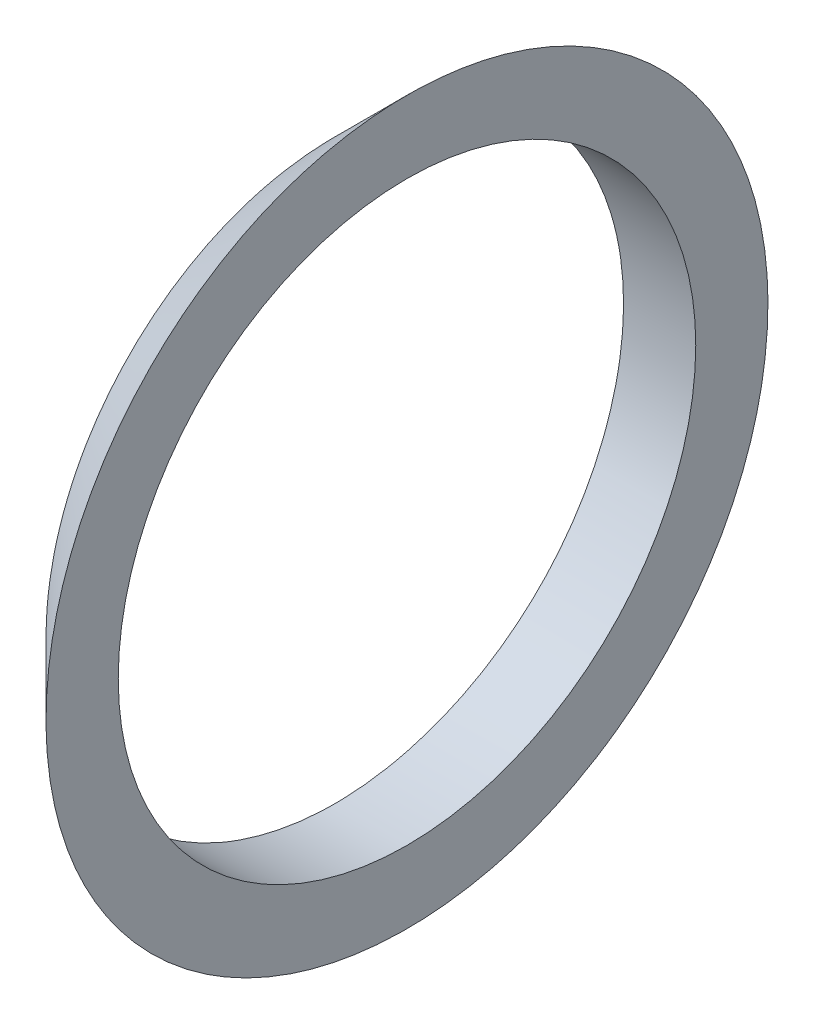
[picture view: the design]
ISO-10303-21;
HEADER;
FILE_DESCRIPTION(('STEP AP214'),'2;1');
FILE_NAME('part.step','',(''),(''),'','','');
FILE_SCHEMA(('AUTOMOTIVE_DESIGN { 1 0 10303 214 1 1 1 1 }'));
ENDSEC;
DATA;
#1=APPLICATION_CONTEXT('core data for automotive mechanical design processes');
#2=APPLICATION_PROTOCOL_DEFINITION('international standard','automotive_design',2000,#1);
#3=PRODUCT_CONTEXT('',#1,'mechanical');
#4=PRODUCT('Part','Part','',(#3));
#5=PRODUCT_RELATED_PRODUCT_CATEGORY('part','',(#4));
#6=PRODUCT_DEFINITION_FORMATION('','',#4);
#7=PRODUCT_DEFINITION_CONTEXT('part definition',#1,'design');
#8=PRODUCT_DEFINITION('design','',#6,#7);
#9=PRODUCT_DEFINITION_SHAPE('','',#8);
#10=(LENGTH_UNIT() NAMED_UNIT(*) SI_UNIT(.MILLI.,.METRE.));
#11=(NAMED_UNIT(*) PLANE_ANGLE_UNIT() SI_UNIT($,.RADIAN.));
#12=(NAMED_UNIT(*) SI_UNIT($,.STERADIAN.) SOLID_ANGLE_UNIT());
#13=UNCERTAINTY_MEASURE_WITH_UNIT(LENGTH_MEASURE(1.E-05),#10,'distance_accuracy_value','');
#14=(GEOMETRIC_REPRESENTATION_CONTEXT(3) GLOBAL_UNCERTAINTY_ASSIGNED_CONTEXT((#13)) GLOBAL_UNIT_ASSIGNED_CONTEXT((#10,
#11,#12)) REPRESENTATION_CONTEXT('',''));
#15=CARTESIAN_POINT('',(0.,0.,0.));
#16=DIRECTION('',(0.,0.,1.));
#17=DIRECTION('',(1.,0.,0.));
#18=AXIS2_PLACEMENT_3D('',#15,#16,#17);
#19=CARTESIAN_POINT('',(112.,55.,-23.));
#20=DIRECTION('',(1.,0.,0.));
#21=DIRECTION('',(0.,0.,-1.));
#22=AXIS2_PLACEMENT_3D('',#19,#20,#21);
#23=PLANE('',#22);
#24=CARTESIAN_POINT('',(112.,0.,19.9998724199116));
#25=CARTESIAN_POINT('',(112.,0.244989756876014,19.9998783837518));
#26=CARTESIAN_POINT('',(112.,0.48995497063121,19.995508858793));
#27=CARTESIAN_POINT('',(112.,0.979565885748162,19.9778506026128));
#28=CARTESIAN_POINT('',(112.,1.22421160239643,19.9645623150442));
#29=CARTESIAN_POINT('',(112.,1.71283709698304,19.9290391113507));
#30=CARTESIAN_POINT('',(112.,1.95681691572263,19.9068047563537));
#31=CARTESIAN_POINT('',(112.,2.44383325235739,19.8534078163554));
#32=CARTESIAN_POINT('',(112.,2.68686957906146,19.8222435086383));
#33=CARTESIAN_POINT('',(112.,3.41415854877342,19.7153111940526));
#34=CARTESIAN_POINT('',(112.,3.89651224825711,19.6261095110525));
#35=CARTESIAN_POINT('',(112.,4.85324910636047,19.4122585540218));
#36=CARTESIAN_POINT('',(112.,5.32763197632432,19.2876079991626));
#37=CARTESIAN_POINT('',(112.,6.3348788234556,18.982590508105));
#38=CARTESIAN_POINT('',(112.,6.86608978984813,18.7967271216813));
#39=CARTESIAN_POINT('',(112.,7.91085705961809,18.3805997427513));
#40=CARTESIAN_POINT('',(112.,8.42441159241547,18.1503313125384));
#41=CARTESIAN_POINT('',(112.,9.4304440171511,17.6471066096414));
#42=CARTESIAN_POINT('',(112.,9.92291258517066,17.37413169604));
#43=CARTESIAN_POINT('',(112.,10.8831031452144,16.7877001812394));
#44=CARTESIAN_POINT('',(112.,11.3508256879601,16.4742444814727));
#45=CARTESIAN_POINT('',(112.,12.2566972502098,15.8104072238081));
#46=CARTESIAN_POINT('',(112.,12.6949465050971,15.4601624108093));
#47=CARTESIAN_POINT('',(112.,13.540730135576,14.7243493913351));
#48=CARTESIAN_POINT('',(112.,13.9482637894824,14.338780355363));
#49=CARTESIAN_POINT('',(112.,14.7297504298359,13.535048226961));
#50=CARTESIAN_POINT('',(112.,15.1037058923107,13.1168875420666));
#51=CARTESIAN_POINT('',(112.,15.8153610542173,12.2507735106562));
#52=CARTESIAN_POINT('',(112.,16.1530612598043,11.8028205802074));
#53=CARTESIAN_POINT('',(112.,16.7926480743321,10.8758849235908));
#54=CARTESIAN_POINT('',(112.,17.0941722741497,10.3966522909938));
#55=CARTESIAN_POINT('',(112.,17.6556360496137,9.41433884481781));
#56=CARTESIAN_POINT('',(112.,17.9155761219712,8.91125831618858));
#57=CARTESIAN_POINT('',(112.,18.2727886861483,8.14162564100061));
#58=CARTESIAN_POINT('',(112.,18.3864218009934,7.88254695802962));
#59=CARTESIAN_POINT('',(112.,18.6025492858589,7.35984065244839));
#60=CARTESIAN_POINT('',(112.,18.7050465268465,7.09621422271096));
#61=CARTESIAN_POINT('',(112.,18.8986326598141,6.56479242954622));
#62=CARTESIAN_POINT('',(112.,18.9897209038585,6.29699683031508));
#63=CARTESIAN_POINT('',(112.,19.1602610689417,5.75772578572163));
#64=CARTESIAN_POINT('',(112.,19.2397130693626,5.48625036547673));
#65=CARTESIAN_POINT('',(112.,19.3860625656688,4.94295472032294));
#66=CARTESIAN_POINT('',(112.,19.4530816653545,4.6711672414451));
#67=CARTESIAN_POINT('',(112.,19.5754672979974,4.12498736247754));
#68=CARTESIAN_POINT('',(112.,19.6308340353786,3.8505950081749));
#69=CARTESIAN_POINT('',(112.,19.7299923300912,3.29971527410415));
#70=CARTESIAN_POINT('',(112.,19.7737832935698,3.02322778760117));
#71=CARTESIAN_POINT('',(112.,19.8498797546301,2.46867316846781));
#72=CARTESIAN_POINT('',(112.,19.8821850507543,2.19060600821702));
#73=CARTESIAN_POINT('',(112.,19.9352950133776,1.63329917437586));
#74=CARTESIAN_POINT('',(112.,19.9560965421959,1.35405920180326));
#75=CARTESIAN_POINT('',(112.,19.9861042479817,0.794960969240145));
#76=CARTESIAN_POINT('',(112.,19.9953106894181,0.515102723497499));
#77=CARTESIAN_POINT('',(112.,20.0019069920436,-0.0447562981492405));
#78=CARTESIAN_POINT('',(112.,19.9992967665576,-0.324757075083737));
#79=CARTESIAN_POINT('',(112.,19.9823608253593,-0.884406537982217));
#80=CARTESIAN_POINT('',(112.,19.9680348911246,-1.1640552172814));
#81=CARTESIAN_POINT('',(112.,19.9276889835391,-1.72455345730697));
#82=CARTESIAN_POINT('',(112.,19.9015846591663,-2.00539694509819));
#83=CARTESIAN_POINT('',(112.,19.8377117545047,-2.56575274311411));
#84=CARTESIAN_POINT('',(112.,19.7999431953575,-2.84526505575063));
#85=CARTESIAN_POINT('',(112.,19.7127211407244,-3.40245829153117));
#86=CARTESIAN_POINT('',(112.,19.6632680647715,-3.68013928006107));
#87=CARTESIAN_POINT('',(112.,19.5525534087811,-4.23311645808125));
#88=CARTESIAN_POINT('',(112.,19.4912919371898,-4.50841266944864));
#89=CARTESIAN_POINT('',(112.,19.289852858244,-5.32976534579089));
#90=CARTESIAN_POINT('',(112.,19.1319720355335,-5.87159756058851));
#91=CARTESIAN_POINT('',(112.,18.7703120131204,-6.93964824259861));
#92=CARTESIAN_POINT('',(112.,18.5665306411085,-7.4658659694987));
#93=CARTESIAN_POINT('',(112.,18.1169595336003,-8.49532083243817));
#94=CARTESIAN_POINT('',(112.,17.871497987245,-8.99870127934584));
#95=CARTESIAN_POINT('',(112.,17.3393324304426,-9.98314516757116));
#96=CARTESIAN_POINT('',(112.,17.0526298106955,-10.4642093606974));
#97=CARTESIAN_POINT('',(112.,16.439817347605,-11.4007904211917));
#98=CARTESIAN_POINT('',(112.,16.1136936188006,-11.8562982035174));
#99=CARTESIAN_POINT('',(112.,15.4245227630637,-12.7384810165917));
#100=CARTESIAN_POINT('',(112.,15.0614744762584,-13.1651551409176));
#101=CARTESIAN_POINT('',(112.,14.2984375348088,-13.9897677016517));
#102=CARTESIAN_POINT('',(112.,13.8982036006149,-14.3874791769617));
#103=CARTESIAN_POINT('',(112.,13.0658328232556,-15.1479663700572));
#104=CARTESIAN_POINT('',(112.,12.6336968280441,-15.5107430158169));
#105=CARTESIAN_POINT('',(112.,11.7405266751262,-16.1985447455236));
#106=CARTESIAN_POINT('',(112.,11.2794999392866,-16.5235794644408));
#107=CARTESIAN_POINT('',(112.,10.331641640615,-17.1335984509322));
#108=CARTESIAN_POINT('',(112.,9.84480886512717,-17.418580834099));
#109=CARTESIAN_POINT('',(112.,8.84763244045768,-17.9471688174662));
#110=CARTESIAN_POINT('',(112.,8.33723378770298,-18.1906706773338));
#111=CARTESIAN_POINT('',(112.,7.29768194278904,-18.6335359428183));
#112=CARTESIAN_POINT('',(112.,6.76853009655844,-18.832902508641));
#113=CARTESIAN_POINT('',(112.,5.69484104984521,-19.1853814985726));
#114=CARTESIAN_POINT('',(112.,5.15030126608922,-19.3384861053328));
#115=CARTESIAN_POINT('',(112.,4.32527090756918,-19.532519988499));
#116=CARTESIAN_POINT('',(112.,4.04885124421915,-19.5912665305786));
#117=CARTESIAN_POINT('',(112.,3.49373972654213,-19.6969307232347));
#118=CARTESIAN_POINT('',(112.,3.21504785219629,-19.7438482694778));
#119=CARTESIAN_POINT('',(112.,2.65960417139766,-19.8254302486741));
#120=CARTESIAN_POINT('',(112.,2.38287459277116,-19.8602467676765));
#121=CARTESIAN_POINT('',(112.,1.82821719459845,-19.9184663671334));
#122=CARTESIAN_POINT('',(112.,1.55028937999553,-19.9418694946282));
#123=CARTESIAN_POINT('',(112.,0.993708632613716,-19.977200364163));
#124=CARTESIAN_POINT('',(112.,0.715055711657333,-19.9891282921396));
#125=CARTESIAN_POINT('',(112.,0.157496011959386,-20.001310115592));
#126=CARTESIAN_POINT('',(112.,-0.121410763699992,-20.0015641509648));
#127=CARTESIAN_POINT('',(112.,-0.678971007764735,-19.9903886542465));
#128=CARTESIAN_POINT('',(112.,-0.957624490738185,-19.9789598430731));
#129=CARTESIAN_POINT('',(112.,-1.51422688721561,-19.944624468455));
#130=CARTESIAN_POINT('',(112.,-1.79217578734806,-19.9217176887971));
#131=CARTESIAN_POINT('',(112.,-2.34689854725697,-19.8644900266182));
#132=CARTESIAN_POINT('',(112.,-2.62367239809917,-19.8301690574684));
#133=CARTESIAN_POINT('',(112.,-3.17556419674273,-19.750120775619));
#134=CARTESIAN_POINT('',(112.,-3.45068216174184,-19.7043935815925));
#135=CARTESIAN_POINT('',(112.,-4.00382788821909,-19.6004656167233));
#136=CARTESIAN_POINT('',(112.,-4.28181531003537,-19.5420497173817));
#137=CARTESIAN_POINT('',(112.,-4.83500087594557,-19.4132332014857));
#138=CARTESIAN_POINT('',(112.,-5.11019901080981,-19.3428325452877));
#139=CARTESIAN_POINT('',(112.,-5.65728173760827,-19.1901677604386));
#140=CARTESIAN_POINT('',(112.,-5.92916636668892,-19.1079037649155));
#141=CARTESIAN_POINT('',(112.,-6.46911992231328,-18.9316841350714));
#142=CARTESIAN_POINT('',(112.,-6.7371888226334,-18.8377284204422));
#143=CARTESIAN_POINT('',(112.,-7.26901323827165,-18.6383752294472));
#144=CARTESIAN_POINT('',(112.,-7.53276915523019,-18.5329788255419));
#145=CARTESIAN_POINT('',(112.,-8.05553219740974,-18.31105190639));
#146=CARTESIAN_POINT('',(112.,-8.31453930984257,-18.1945213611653));
#147=CARTESIAN_POINT('',(112.,-9.08376330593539,-17.8285542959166));
#148=CARTESIAN_POINT('',(112.,-9.58629391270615,-17.5627006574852));
#149=CARTESIAN_POINT('',(112.,-10.5579438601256,-16.9945384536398));
#150=CARTESIAN_POINT('',(112.,-11.0275052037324,-16.6929825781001));
#151=CARTESIAN_POINT('',(112.,-11.9398222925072,-16.051731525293));
#152=CARTESIAN_POINT('',(112.,-12.3825789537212,-15.7120376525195));
#153=CARTESIAN_POINT('',(112.,-13.2384182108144,-14.9969924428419));
#154=CARTESIAN_POINT('',(112.,-13.6514953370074,-14.6216345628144));
#155=CARTESIAN_POINT('',(112.,-14.44516187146,-13.8380045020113));
#156=CARTESIAN_POINT('',(112.,-14.8257507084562,-13.4297317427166));
#157=CARTESIAN_POINT('',(112.,-15.5566349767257,-12.5772719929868));
#158=CARTESIAN_POINT('',(112.,-15.9064521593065,-12.1326746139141));
#159=CARTESIAN_POINT('',(112.,-16.5672335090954,-11.2154991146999));
#160=CARTESIAN_POINT('',(112.,-16.8781969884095,-10.7429204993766));
#161=CARTESIAN_POINT('',(112.,-17.4589941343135,-9.77323809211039));
#162=CARTESIAN_POINT('',(112.,-17.7288402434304,-9.27614177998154));
#163=CARTESIAN_POINT('',(112.,-18.1013076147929,-8.51487393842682));
#164=CARTESIAN_POINT('',(112.,-18.2200899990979,-8.25848776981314));
#165=CARTESIAN_POINT('',(112.,-18.4466999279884,-7.74089752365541));
#166=CARTESIAN_POINT('',(112.,-18.5545274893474,-7.47969345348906));
#167=CARTESIAN_POINT('',(112.,-18.7585971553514,-6.95378012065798));
#168=CARTESIAN_POINT('',(112.,-18.85487582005,-6.68908503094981));
#169=CARTESIAN_POINT('',(112.,-19.0359969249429,-6.1558090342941));
#170=CARTESIAN_POINT('',(112.,-19.1208393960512,-5.88722813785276));
#171=CARTESIAN_POINT('',(112.,-19.2789004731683,-5.34666593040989));
#172=CARTESIAN_POINT('',(112.,-19.3521190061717,-5.07468459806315));
#173=CARTESIAN_POINT('',(112.,-19.4868037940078,-4.52782847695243));
#174=CARTESIAN_POINT('',(112.,-19.548270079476,-4.25295369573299));
#175=CARTESIAN_POINT('',(112.,-19.6594315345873,-3.70075013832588));
#176=CARTESIAN_POINT('',(112.,-19.7091231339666,-3.42342064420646));
#177=CARTESIAN_POINT('',(112.,-19.7968457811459,-2.866924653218));
#178=CARTESIAN_POINT('',(112.,-19.8348767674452,-2.58775814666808));
#179=CARTESIAN_POINT('',(112.,-19.8993005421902,-2.02808096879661));
#180=CARTESIAN_POINT('',(112.,-19.9256931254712,-1.74757027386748));
#181=CARTESIAN_POINT('',(112.,-19.9667892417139,-1.18569816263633));
#182=CARTESIAN_POINT('',(112.,-19.9814929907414,-0.904336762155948));
#183=CARTESIAN_POINT('',(112.,-19.9989999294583,-0.34269580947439));
#184=CARTESIAN_POINT('',(112.,-20.0018641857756,-0.0624181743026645));
#185=CARTESIAN_POINT('',(112.,-19.9957492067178,0.49800718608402));
#186=CARTESIAN_POINT('',(112.,-19.9867699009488,0.778154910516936));
#187=CARTESIAN_POINT('',(112.,-19.9571896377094,1.33783814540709));
#188=CARTESIAN_POINT('',(112.,-19.9365887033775,1.61737365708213));
#189=CARTESIAN_POINT('',(112.,-19.8838519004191,2.17533788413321));
#190=CARTESIAN_POINT('',(112.,-19.8517159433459,2.45376659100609));
#191=CARTESIAN_POINT('',(112.,-19.7380586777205,3.28650506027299));
#192=CARTESIAN_POINT('',(112.,-19.6392721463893,3.83856629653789));
#193=CARTESIAN_POINT('',(112.,-19.3949503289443,4.93223120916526));
#194=CARTESIAN_POINT('',(112.,-19.2494183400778,5.47383562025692));
#195=CARTESIAN_POINT('',(112.,-18.9966141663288,6.27613268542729));
#196=CARTESIAN_POINT('',(112.,-18.9064183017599,6.54230920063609));
#197=CARTESIAN_POINT('',(112.,-18.7147568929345,7.07057086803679));
#198=CARTESIAN_POINT('',(112.,-18.6132913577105,7.3326560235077));
#199=CARTESIAN_POINT('',(112.,-18.2924069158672,8.11214604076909));
#200=CARTESIAN_POINT('',(112.,-18.0564758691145,8.62286235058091));
#201=CARTESIAN_POINT('',(112.,-17.5425219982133,9.62270405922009));
#202=CARTESIAN_POINT('',(112.,-17.2644903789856,10.1118249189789));
#203=CARTESIAN_POINT('',(112.,-16.6682719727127,11.0649443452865));
#204=CARTESIAN_POINT('',(112.,-16.3500872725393,11.5289442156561));
#205=CARTESIAN_POINT('',(112.,-15.6765851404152,12.4276112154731));
#206=CARTESIAN_POINT('',(112.,-15.3213466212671,12.8623375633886));
#207=CARTESIAN_POINT('',(112.,-14.5757531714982,13.7006568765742));
#208=CARTESIAN_POINT('',(112.,-14.1853979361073,14.1042495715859));
#209=CARTESIAN_POINT('',(112.,-13.5757023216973,14.6841373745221));
#210=CARTESIAN_POINT('',(112.,-13.368390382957,14.8732256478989));
#211=CARTESIAN_POINT('',(112.,-12.9461062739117,15.2425342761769));
#212=CARTESIAN_POINT('',(112.,-12.7311360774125,15.4227568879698));
#213=CARTESIAN_POINT('',(112.,-12.0751694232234,15.9497291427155));
#214=CARTESIAN_POINT('',(112.,-11.6230736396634,16.282824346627));
#215=CARTESIAN_POINT('',(112.,-10.6884257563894,16.9127517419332));
#216=CARTESIAN_POINT('',(112.,-10.2056361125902,17.2092304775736));
#217=CARTESIAN_POINT('',(112.,-9.21658508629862,17.7601644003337));
#218=CARTESIAN_POINT('',(112.,-8.71032253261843,18.0146174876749));
#219=CARTESIAN_POINT('',(112.,-7.67839329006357,18.4792434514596));
#220=CARTESIAN_POINT('',(112.,-7.15274322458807,18.6894532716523));
#221=CARTESIAN_POINT('',(112.,-6.0854595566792,19.0641708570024));
#222=CARTESIAN_POINT('',(112.,-5.54382897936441,19.2286872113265));
#223=CARTESIAN_POINT('',(112.,-4.58872093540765,19.4747306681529));
#224=CARTESIAN_POINT('',(112.,-4.17790054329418,19.5667215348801));
#225=CARTESIAN_POINT('',(112.,-3.35122502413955,19.7244487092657));
#226=CARTESIAN_POINT('',(112.,-2.93537021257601,19.7901866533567));
#227=CARTESIAN_POINT('',(112.,-2.30917935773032,19.8689853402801));
#228=CARTESIAN_POINT('',(112.,-2.10004239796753,19.8919505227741));
#229=CARTESIAN_POINT('',(112.,-1.6811827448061,19.9313074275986));
#230=CARTESIAN_POINT('',(112.,-1.47146014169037,19.9477001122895));
#231=CARTESIAN_POINT('',(112.,-0.841581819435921,19.9869460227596));
#232=CARTESIAN_POINT('',(112.,-0.42075471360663,19.9998621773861));
#233=CARTESIAN_POINT('',(112.,0.,19.9998724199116));
#234=B_SPLINE_CURVE_WITH_KNOTS('',3,(#24,#25,#26,#27,#28,#29,#30,#31,#32,#33,#34,#35,#36,#37,
#38,#39,#40,#41,#42,#43,#44,#45,#46,#47,#48,#49,#50,#51,#52,#53,#54,#55,#56,#57,#58,#59,#60,#61,
#62,#63,#64,#65,#66,#67,#68,#69,#70,#71,#72,#73,#74,#75,#76,#77,#78,#79,#80,#81,#82,#83,#84,#85,
#86,#87,#88,#89,#90,#91,#92,#93,#94,#95,#96,#97,#98,#99,#100,#101,#102,#103,#104,#105,#106,#107,
#108,#109,#110,#111,#112,#113,#114,#115,#116,#117,#118,#119,#120,#121,#122,#123,#124,#125,#126,
#127,#128,#129,#130,#131,#132,#133,#134,#135,#136,#137,#138,#139,#140,#141,#142,#143,#144,#145,
#146,#147,#148,#149,#150,#151,#152,#153,#154,#155,#156,#157,#158,#159,#160,#161,#162,#163,#164,
#165,#166,#167,#168,#169,#170,#171,#172,#173,#174,#175,#176,#177,#178,#179,#180,#181,#182,#183,
#184,#185,#186,#187,#188,#189,#190,#191,#192,#193,#194,#195,#196,#197,#198,#199,#200,#201,#202,
#203,#204,#205,#206,#207,#208,#209,#210,#211,#212,#213,#214,#215,#216,#217,#218,#219,#220,#221,
#222,#223,#224,#225,#226,#227,#228,#229,#230,#231,#232,#233),.UNSPECIFIED.,.T.,.F.,(4,2,2,2,2,2,
2,2,2,2,2,2,2,2,2,2,2,2,2,2,2,2,2,2,2,2,2,2,2,2,2,2,2,2,2,2,2,2,2,2,2,2,2,2,2,2,2,2,2,2,2,2,2,2,
2,2,2,2,2,2,2,2,2,2,2,2,2,2,2,2,2,2,2,2,2,2,2,2,2,2,2,2,2,2,2,2,2,2,2,2,2,2,2,2,2,2,2,2,2,2,2,2,
2,2,4),(0.,0.734884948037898,1.46973334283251,2.20453565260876,2.93947981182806,
4.40960497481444,5.87978326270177,7.5660558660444,9.25249707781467,10.9396764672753,
12.6268182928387,14.3078971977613,15.9890155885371,17.6700099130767,19.350980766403,
21.0475900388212,22.7441790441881,23.5926803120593,24.4409623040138,25.2892924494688,
26.1376168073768,26.9771473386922,27.8166631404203,28.6562220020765,29.4957955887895,
30.3355980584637,31.1753813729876,32.0151708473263,32.854975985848,33.7008932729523,
34.5468090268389,35.3926944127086,36.2385720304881,37.9293840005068,39.6202760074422,
41.2984239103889,42.9765152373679,44.6551993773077,46.3339362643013,48.0246610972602,
49.7153410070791,51.405588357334,53.0959152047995,54.7904092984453,56.4847820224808,
58.1794409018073,59.0270086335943,59.8745838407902,60.7110848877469,61.5475824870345,
62.3840665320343,63.2205405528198,64.0569629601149,64.8934011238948,65.7298456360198,
66.5662814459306,67.4181926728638,68.2701067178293,69.1220112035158,69.9739215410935,
70.8257520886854,71.6775849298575,73.3808958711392,75.0531641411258,76.7253752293,
78.3978937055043,80.0704415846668,81.7655657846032,83.460719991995,85.1553602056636,
86.0028492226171,86.8503369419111,87.6950667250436,88.5397942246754,89.3845270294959,
90.2292576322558,91.0742440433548,91.9192349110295,92.7642406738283,93.6092308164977,
94.4498571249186,95.2904884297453,96.1311180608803,96.9717541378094,98.6521304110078,
100.332388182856,101.17529220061,102.018195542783,103.703761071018,105.389679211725,
107.075509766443,108.75782063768,110.440146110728,111.28171507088,112.123068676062,
113.805597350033,115.503273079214,117.201033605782,118.897370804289,120.593388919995,
121.855590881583,123.11771415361,123.748807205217,124.379807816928,125.641927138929),.UNSPECIFIED.);
#235=CARTESIAN_POINT('',(112.,0.,19.9998724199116));
#236=VERTEX_POINT('',#235);
#237=EDGE_CURVE('E43',#236,#236,#234,.T.);
#238=ORIENTED_EDGE('',*,*,#237,.F.);
#239=EDGE_LOOP('',(#238));
#240=FACE_BOUND('',#239,.T.);
#241=CARTESIAN_POINT('',(112.,0.,0.));
#242=DIRECTION('',(1.,0.,0.));
#243=DIRECTION('',(0.,1.,0.));
#244=AXIS2_PLACEMENT_3D('',#241,#242,#243);
#245=CIRCLE('',#244,16.);
#246=CARTESIAN_POINT('',(112.,16.,0.));
#247=VERTEX_POINT('',#246);
#248=EDGE_CURVE('E48',#247,#247,#245,.T.);
#249=ORIENTED_EDGE('',*,*,#248,.F.);
#250=EDGE_LOOP('',(#249));
#251=FACE_BOUND('',#250,.T.);
#252=ADVANCED_FACE('F29',(#240,#251),#23,.T.);
#253=CARTESIAN_POINT('',(-128.,0.,0.));
#254=DIRECTION('',(-1.,0.,0.));
#255=DIRECTION('',(0.,0.0562040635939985,0.998419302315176));
#256=AXIS2_PLACEMENT_3D('',#253,#254,#255);
#257=CYLINDRICAL_SURFACE('',#256,16.);
#258=ORIENTED_EDGE('',*,*,#248,.T.);
#259=EDGE_LOOP('',(#258));
#260=FACE_BOUND('',#259,.T.);
#261=CARTESIAN_POINT('',(108.000102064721,4.43824598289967E-12,16.));
#262=CARTESIAN_POINT('',(108.000099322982,-0.22474689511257,16.0000002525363));
#263=CARTESIAN_POINT('',(107.999957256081,-0.449486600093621,15.9952640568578));
#264=CARTESIAN_POINT('',(107.999621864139,-0.898570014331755,15.9763286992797));
#265=CARTESIAN_POINT('',(107.99942853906,-1.12291372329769,15.9621295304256));
#266=CARTESIAN_POINT('',(107.998998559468,-1.5708387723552,15.9242891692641));
#267=CARTESIAN_POINT('',(107.998761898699,-1.7944199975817,15.9006466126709));
#268=CARTESIAN_POINT('',(107.998296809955,-2.24042725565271,15.8439593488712));
#269=CARTESIAN_POINT('',(107.998068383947,-2.46285300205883,15.8109124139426));
#270=CARTESIAN_POINT('',(107.997456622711,-3.12814494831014,15.6976794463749));
#271=CARTESIAN_POINT('',(107.997147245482,-3.56869782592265,15.6034289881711));
#272=CARTESIAN_POINT('',(107.996863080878,-4.44028724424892,15.3781164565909));
#273=CARTESIAN_POINT('',(107.996888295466,-4.87132372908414,15.2470541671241));
#274=CARTESIAN_POINT('',(107.997162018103,-5.50827915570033,15.0236317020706));
#275=CARTESIAN_POINT('',(107.997292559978,-5.71898465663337,14.9446919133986));
#276=CARTESIAN_POINT('',(107.997618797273,-6.13682572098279,14.7780226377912));
#277=CARTESIAN_POINT('',(107.99781447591,-6.34396218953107,14.6902954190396));
#278=CARTESIAN_POINT('',(107.998475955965,-6.95958727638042,14.414103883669));
#279=CARTESIAN_POINT('',(107.999016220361,-7.36232466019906,14.2126180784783));
#280=CARTESIAN_POINT('',(108.000134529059,-8.14923822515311,13.7765122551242));
#281=CARTESIAN_POINT('',(108.000712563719,-8.53341910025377,13.5419006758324));
#282=CARTESIAN_POINT('',(108.001744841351,-9.28066692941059,13.0411454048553));
#283=CARTESIAN_POINT('',(108.00219908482,-9.64373396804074,12.7750018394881));
#284=CARTESIAN_POINT('',(108.00286299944,-10.346196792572,12.2130486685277));
#285=CARTESIAN_POINT('',(108.003072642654,-10.6855898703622,11.9172356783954));
#286=CARTESIAN_POINT('',(108.00318416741,-11.3382516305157,11.298069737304));
#287=CARTESIAN_POINT('',(108.003086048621,-11.6515202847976,10.9747167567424));
#288=CARTESIAN_POINT('',(108.002638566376,-12.2497160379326,10.3027573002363));
#289=CARTESIAN_POINT('',(108.002289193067,-12.5346420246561,9.95414983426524));
#290=CARTESIAN_POINT('',(108.001491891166,-13.0741130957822,9.23417112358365));
#291=CARTESIAN_POINT('',(108.001043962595,-13.3286581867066,8.86279988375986));
#292=CARTESIAN_POINT('',(108.000102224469,-13.8055504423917,8.09994523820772));
#293=CARTESIAN_POINT('',(107.999608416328,-14.0278985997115,7.70846245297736));
#294=CARTESIAN_POINT('',(107.998526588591,-14.438825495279,6.90815888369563));
#295=CARTESIAN_POINT('',(107.99793856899,-14.6274042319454,6.49933809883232));
#296=CARTESIAN_POINT('',(107.99688594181,-14.9694518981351,5.66725991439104));
#297=CARTESIAN_POINT('',(107.996421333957,-15.1229209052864,5.24400254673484));
#298=CARTESIAN_POINT('',(107.996203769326,-15.3936566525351,4.38608022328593));
#299=CARTESIAN_POINT('',(107.996450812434,-15.510923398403,3.95141526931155));
#300=CARTESIAN_POINT('',(107.997564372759,-15.7084262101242,3.07369754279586));
#301=CARTESIAN_POINT('',(107.998430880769,-15.7886628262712,2.63064489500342));
#302=CARTESIAN_POINT('',(107.999340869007,-15.8808066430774,1.96230023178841));
#303=CARTESIAN_POINT('',(107.999579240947,-15.9068207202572,1.73886602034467));
#304=CARTESIAN_POINT('',(107.999902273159,-15.9494094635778,1.29108422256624));
#305=CARTESIAN_POINT('',(107.999986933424,-15.9659841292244,1.06673663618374));
#306=CARTESIAN_POINT('',(108.000040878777,-15.9896599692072,0.617546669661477));
#307=CARTESIAN_POINT('',(108.000010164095,-15.9967611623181,0.392704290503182));
#308=CARTESIAN_POINT('',(108.000000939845,-16.0014787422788,-0.057080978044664));
#309=CARTESIAN_POINT('',(108.00002243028,-15.9990951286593,-0.282023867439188));
#310=CARTESIAN_POINT('',(108.000029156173,-15.9848469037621,-0.731609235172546));
#311=CARTESIAN_POINT('',(108.00001439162,-15.9729822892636,-0.956251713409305));
#312=CARTESIAN_POINT('',(107.999837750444,-15.9397936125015,-1.40483579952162));
#313=CARTESIAN_POINT('',(107.999675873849,-15.9184695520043,-1.62877740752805));
#314=CARTESIAN_POINT('',(107.99920357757,-15.8663994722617,-2.0755580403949));
#315=CARTESIAN_POINT('',(107.99889316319,-15.8356537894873,-2.29839710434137));
#316=CARTESIAN_POINT('',(107.998192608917,-15.7647968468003,-2.74258688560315));
#317=CARTESIAN_POINT('',(107.997802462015,-15.7246847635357,-2.96393747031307));
#318=CARTESIAN_POINT('',(107.996802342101,-15.5904047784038,-3.62511586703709));
#319=CARTESIAN_POINT('',(107.996362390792,-15.4822791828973,-4.0621899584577));
#320=CARTESIAN_POINT('',(107.996235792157,-15.2295814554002,-4.92566941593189));
#321=CARTESIAN_POINT('',(107.996549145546,-15.0850092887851,-5.35207477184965));
#322=CARTESIAN_POINT('',(107.997267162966,-14.8416434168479,-5.98132454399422));
#323=CARTESIAN_POINT('',(107.997547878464,-14.7560925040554,-6.18937071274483));
#324=CARTESIAN_POINT('',(107.998105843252,-14.5762997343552,-6.60167168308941));
#325=CARTESIAN_POINT('',(107.998383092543,-14.4820578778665,-6.80592648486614));
#326=CARTESIAN_POINT('',(107.999197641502,-14.1865405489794,-7.41243918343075));
#327=CARTESIAN_POINT('',(107.999717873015,-13.9724371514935,-7.80853885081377));
#328=CARTESIAN_POINT('',(108.000698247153,-13.5116509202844,-8.58124158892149));
#329=CARTESIAN_POINT('',(108.001158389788,-13.2649680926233,-8.95784466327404));
#330=CARTESIAN_POINT('',(108.002026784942,-12.7407470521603,-9.68894540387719));
#331=CARTESIAN_POINT('',(108.002435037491,-12.4632088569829,-10.0434430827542));
#332=CARTESIAN_POINT('',(108.002999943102,-11.8792575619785,-10.7277949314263));
#333=CARTESIAN_POINT('',(108.003156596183,-11.5728444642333,-11.0576491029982));
#334=CARTESIAN_POINT('',(108.0031150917,-10.9333156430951,-11.6903784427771));
#335=CARTESIAN_POINT('',(108.002916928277,-10.6001994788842,-11.9932531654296));
#336=CARTESIAN_POINT('',(108.002292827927,-9.90963301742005,-12.569864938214));
#337=CARTESIAN_POINT('',(108.001866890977,-9.55218271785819,-12.8436019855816));
#338=CARTESIAN_POINT('',(108.000979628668,-8.81550686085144,-13.3599851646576));
#339=CARTESIAN_POINT('',(108.000518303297,-8.4362812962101,-13.6026312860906));
#340=CARTESIAN_POINT('',(107.999525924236,-7.65868383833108,-14.0551361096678));
#341=CARTESIAN_POINT('',(107.998994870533,-7.26031194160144,-14.2649948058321));
#342=CARTESIAN_POINT('',(107.998171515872,-6.65066099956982,-14.5540145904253));
#343=CARTESIAN_POINT('',(107.997892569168,-6.44540479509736,-14.6460686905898));
#344=CARTESIAN_POINT('',(107.997341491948,-6.03120116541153,-14.8214439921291));
#345=CARTESIAN_POINT('',(107.997069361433,-5.82225374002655,-14.9047651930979));
#346=CARTESIAN_POINT('',(107.996415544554,-5.19040154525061,-15.1413966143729));
#347=CARTESIAN_POINT('',(107.996196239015,-4.76239593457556,-15.2814177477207));
#348=CARTESIAN_POINT('',(107.996410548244,-4.11286446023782,-15.4639909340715));
#349=CARTESIAN_POINT('',(107.996572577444,-3.89507550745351,-15.5202769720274));
#350=CARTESIAN_POINT('',(107.997058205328,-3.45729836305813,-15.6236244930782));
#351=CARTESIAN_POINT('',(107.997381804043,-3.23731017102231,-15.6706859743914));
#352=CARTESIAN_POINT('',(107.99808851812,-2.79555068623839,-15.7554908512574));
#353=CARTESIAN_POINT('',(107.998471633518,-2.57377939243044,-15.7932342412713));
#354=CARTESIAN_POINT('',(107.999130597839,-2.1288412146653,-15.8593384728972));
#355=CARTESIAN_POINT('',(107.99940644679,-1.90567433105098,-15.8876993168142));
#356=CARTESIAN_POINT('',(107.999804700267,-1.45834733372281,-15.9349869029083));
#357=CARTESIAN_POINT('',(107.999927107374,-1.23418723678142,-15.9539138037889));
#358=CARTESIAN_POINT('',(108.000036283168,-0.785268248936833,-15.9823007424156));
#359=CARTESIAN_POINT('',(108.000023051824,-0.560509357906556,-15.9917607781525));
#360=CARTESIAN_POINT('',(108.000010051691,-0.110792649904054,-16.0011970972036));
#361=CARTESIAN_POINT('',(108.000010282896,0.114165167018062,-16.0011733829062));
#362=CARTESIAN_POINT('',(108.000023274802,0.563879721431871,-15.9916422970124));
#363=CARTESIAN_POINT('',(108.000036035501,0.788636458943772,-15.9821349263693));
#364=CARTESIAN_POINT('',(107.999925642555,1.23754960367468,-15.9536533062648));
#365=CARTESIAN_POINT('',(107.999802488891,1.46170601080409,-15.9346790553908));
#366=CARTESIAN_POINT('',(107.999402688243,1.90901845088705,-15.8872978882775));
#367=CARTESIAN_POINT('',(107.999126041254,2.13217448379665,-15.8588909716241));
#368=CARTESIAN_POINT('',(107.99846637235,2.57709430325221,-15.7926933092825));
#369=CARTESIAN_POINT('',(107.998083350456,2.79885809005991,-15.7549025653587));
#370=CARTESIAN_POINT('',(107.997376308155,3.24058077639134,-15.6700107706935));
#371=CARTESIAN_POINT('',(107.997052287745,3.46053967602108,-15.6229097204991));
#372=CARTESIAN_POINT('',(107.996331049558,4.11713082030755,-15.4677537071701));
#373=CARTESIAN_POINT('',(107.996184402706,4.55057540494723,-15.3458313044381));
#374=CARTESIAN_POINT('',(107.996557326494,5.40559284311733,-15.065921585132));
#375=CARTESIAN_POINT('',(107.99707689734,5.82716569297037,-14.9079342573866));
#376=CARTESIAN_POINT('',(107.998165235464,6.65551986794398,-14.5570035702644));
#377=CARTESIAN_POINT('',(107.998734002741,7.06230119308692,-14.3640602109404));
#378=CARTESIAN_POINT('',(107.999786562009,7.85816000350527,-13.944592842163));
#379=CARTESIAN_POINT('',(108.000270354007,8.24723749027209,-13.7180688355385));
#380=CARTESIAN_POINT('',(108.001213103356,9.00492391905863,-13.2330522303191));
#381=CARTESIAN_POINT('',(108.001672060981,9.37353308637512,-12.9745599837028));
#382=CARTESIAN_POINT('',(108.002466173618,10.0876656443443,-12.427442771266));
#383=CARTESIAN_POINT('',(108.002801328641,10.433189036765,-12.1388178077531));
#384=CARTESIAN_POINT('',(108.003159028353,11.0986941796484,-11.5334867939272));
#385=CARTESIAN_POINT('',(108.003181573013,11.4186759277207,-11.2167807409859));
#386=CARTESIAN_POINT('',(108.002898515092,12.0308226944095,-10.5575393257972));
#387=CARTESIAN_POINT('',(108.002592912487,12.3229877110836,-10.2150039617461));
#388=CARTESIAN_POINT('',(108.00183200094,12.8774280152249,-9.50653368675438));
#389=CARTESIAN_POINT('',(108.001376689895,13.1397028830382,-9.1405984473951));
#390=CARTESIAN_POINT('',(108.000444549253,13.6324934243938,-8.38793557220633));
#391=CARTESIAN_POINT('',(107.999967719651,13.8630090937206,-8.00120793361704));
#392=CARTESIAN_POINT('',(107.998935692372,14.2906432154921,-7.20970465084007));
#393=CARTESIAN_POINT('',(107.998380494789,14.4877617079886,-6.80492902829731));
#394=CARTESIAN_POINT('',(107.997265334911,14.8471964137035,-5.98022767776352));
#395=CARTESIAN_POINT('',(107.996705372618,15.0095126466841,-5.56030195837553));
#396=CARTESIAN_POINT('',(107.996198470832,15.2982063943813,-4.70820165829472));
#397=CARTESIAN_POINT('',(107.996251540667,15.4245833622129,-4.27602689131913));
#398=CARTESIAN_POINT('',(107.996850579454,15.586488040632,-3.62105449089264));
#399=CARTESIAN_POINT('',(107.997136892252,15.6358500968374,-3.40158715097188));
#400=CARTESIAN_POINT('',(107.997811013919,15.725282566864,-2.96075188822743));
#401=CARTESIAN_POINT('',(107.998198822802,15.7653529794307,-2.73938396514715));
#402=CARTESIAN_POINT('',(107.998897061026,15.8361244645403,-2.29515904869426));
#403=CARTESIAN_POINT('',(107.999207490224,15.8668255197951,-2.07230205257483));
#404=CARTESIAN_POINT('',(107.99967886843,15.9188053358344,-1.62549068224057));
#405=CARTESIAN_POINT('',(107.999839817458,15.9400840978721,-1.40153630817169));
#406=CARTESIAN_POINT('',(108.00001495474,15.9731809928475,-0.95292992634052));
#407=CARTESIAN_POINT('',(108.000029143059,15.9849991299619,-0.728277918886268));
#408=CARTESIAN_POINT('',(108.000022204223,15.9991539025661,-0.278675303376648));
#409=CARTESIAN_POINT('',(108.000001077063,16.0014905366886,-0.0537246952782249));
#410=CARTESIAN_POINT('',(108.000010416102,15.9966781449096,0.396071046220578));
#411=CARTESIAN_POINT('',(108.000040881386,15.9895292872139,0.620916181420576));
#412=CARTESIAN_POINT('',(107.999986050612,15.9657589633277,1.07010505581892));
#413=CARTESIAN_POINT('',(107.999900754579,15.9491374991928,1.29444879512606));
#414=CARTESIAN_POINT('',(107.99957589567,15.9064513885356,1.74223634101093));
#415=CARTESIAN_POINT('',(107.999336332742,15.8803867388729,1.96568014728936));
#416=CARTESIAN_POINT('',(107.998729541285,15.8188611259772,2.41126911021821));
#417=CARTESIAN_POINT('',(107.998362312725,15.7834001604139,2.63341426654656));
#418=CARTESIAN_POINT('',(107.997639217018,15.7031430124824,3.07601644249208));
#419=CARTESIAN_POINT('',(107.997283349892,15.6583468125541,3.29647345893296));
#420=CARTESIAN_POINT('',(107.996723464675,15.5595057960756,3.73528866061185));
#421=CARTESIAN_POINT('',(107.996519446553,15.5054609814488,3.95364684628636));
#422=CARTESIAN_POINT('',(107.996181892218,15.329584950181,4.6049970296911));
#423=CARTESIAN_POINT('',(107.996322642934,15.1939942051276,5.0343635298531));
#424=CARTESIAN_POINT('',(107.997070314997,14.8871400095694,5.88009313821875));
#425=CARTESIAN_POINT('',(107.997677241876,14.7158761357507,6.29645609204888));
#426=CARTESIAN_POINT('',(107.998818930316,14.3388772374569,7.11329060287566));
#427=CARTESIAN_POINT('',(107.999353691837,14.1331421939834,7.5137621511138));
#428=CARTESIAN_POINT('',(108.000350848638,13.6886767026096,8.29593086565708));
#429=CARTESIAN_POINT('',(108.000813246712,13.4499475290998,8.67762875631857));
#430=CARTESIAN_POINT('',(108.001696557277,12.9411838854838,9.41955839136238));
#431=CARTESIAN_POINT('',(108.002117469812,12.6711494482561,9.77979015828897));
#432=CARTESIAN_POINT('',(108.002775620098,12.1017185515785,10.4761968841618));
#433=CARTESIAN_POINT('',(108.003012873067,11.8023245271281,10.8123738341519));
#434=CARTESIAN_POINT('',(108.003191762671,11.1762824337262,11.4583159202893));
#435=CARTESIAN_POINT('',(108.00313339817,10.8496342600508,11.7680809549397));
#436=CARTESIAN_POINT('',(108.002730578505,10.1713201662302,12.3590712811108));
#437=CARTESIAN_POINT('',(108.002386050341,9.81964788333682,12.6402892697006));
#438=CARTESIAN_POINT('',(108.001506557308,9.09386585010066,13.1720914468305));
#439=CARTESIAN_POINT('',(108.000971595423,8.71975645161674,13.4226761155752));
#440=CARTESIAN_POINT('',(107.999855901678,7.95157782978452,13.8915438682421));
#441=CARTESIAN_POINT('',(107.999275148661,7.55749941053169,14.1098118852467));
#442=CARTESIAN_POINT('',(107.998235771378,6.75234080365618,14.5123556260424));
#443=CARTESIAN_POINT('',(107.997777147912,6.34126050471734,14.6966311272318));
#444=CARTESIAN_POINT('',(107.997127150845,5.50549268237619,15.0296945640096));
#445=CARTESIAN_POINT('',(107.996935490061,5.08082028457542,15.17852049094));
#446=CARTESIAN_POINT('',(107.996894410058,4.2205193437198,15.4398576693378));
#447=CARTESIAN_POINT('',(107.997044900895,3.78489370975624,15.5523784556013));
#448=CARTESIAN_POINT('',(107.997516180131,3.07071293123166,15.7050845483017));
#449=CARTESIAN_POINT('',(107.997751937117,2.79452043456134,15.7565721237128));
#450=CARTESIAN_POINT('',(107.998293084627,2.23981522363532,15.8449383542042));
#451=CARTESIAN_POINT('',(107.998598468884,1.96130272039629,15.8818183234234));
#452=CARTESIAN_POINT('',(107.99916160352,1.40274723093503,15.9408649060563));
#453=CARTESIAN_POINT('',(107.999419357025,1.122704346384,15.9630324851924));
#454=CARTESIAN_POINT('',(107.999891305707,0.561770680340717,15.9926015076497));
#455=CARTESIAN_POINT('',(108.000105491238,0.280879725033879,15.9999996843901));
#456=CARTESIAN_POINT('',(108.000102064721,4.43824598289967E-12,16.));
#457=B_SPLINE_CURVE_WITH_KNOTS('',3,(#261,#262,#263,#264,#265,#266,#267,#268,#269,#270,#271,
#272,#273,#274,#275,#276,#277,#278,#279,#280,#281,#282,#283,#284,#285,#286,#287,#288,#289,#290,
#291,#292,#293,#294,#295,#296,#297,#298,#299,#300,#301,#302,#303,#304,#305,#306,#307,#308,#309,
#310,#311,#312,#313,#314,#315,#316,#317,#318,#319,#320,#321,#322,#323,#324,#325,#326,#327,#328,
#329,#330,#331,#332,#333,#334,#335,#336,#337,#338,#339,#340,#341,#342,#343,#344,#345,#346,#347,
#348,#349,#350,#351,#352,#353,#354,#355,#356,#357,#358,#359,#360,#361,#362,#363,#364,#365,#366,
#367,#368,#369,#370,#371,#372,#373,#374,#375,#376,#377,#378,#379,#380,#381,#382,#383,#384,#385,
#386,#387,#388,#389,#390,#391,#392,#393,#394,#395,#396,#397,#398,#399,#400,#401,#402,#403,#404,
#405,#406,#407,#408,#409,#410,#411,#412,#413,#414,#415,#416,#417,#418,#419,#420,#421,#422,#423,
#424,#425,#426,#427,#428,#429,#430,#431,#432,#433,#434,#435,#436,#437,#438,#439,#440,#441,#442,
#443,#444,#445,#446,#447,#448,#449,#450,#451,#452,#453,#454,#455,#456),.UNSPECIFIED.,.T.,.F.,(4,
2,2,2,2,2,2,2,2,2,2,2,2,2,2,2,2,2,2,2,2,2,2,2,2,2,2,2,2,2,2,2,2,2,2,2,2,2,2,2,2,2,2,2,2,2,2,2,2,
2,2,2,2,2,2,2,2,2,2,2,2,2,2,2,2,2,2,2,2,2,2,2,2,2,2,2,2,2,2,2,2,2,2,2,2,2,2,2,2,2,2,2,2,2,2,2,2,
4),(0.,0.674177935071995,1.34835636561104,2.02263222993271,2.69706795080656,4.04692381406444,
5.39678760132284,6.0716336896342,6.74630603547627,8.09554587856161,9.44444261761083,
10.793333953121,12.1423793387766,13.4914261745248,14.8405259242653,16.1896253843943,
17.5386832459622,18.8877411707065,20.2367961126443,21.5858508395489,22.9348855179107,
23.6095528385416,24.28422019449,24.9588862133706,25.6335522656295,26.3082185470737,
26.9828847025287,27.6575267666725,28.3322281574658,29.6812707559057,31.0303146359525,
31.7049870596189,32.3796594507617,33.7287045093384,35.0777493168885,36.4267933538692,
37.775837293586,39.1249035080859,40.4739698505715,41.8230366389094,43.1721036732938,
43.8467886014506,44.5214735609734,45.8705425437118,46.5452269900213,47.2199115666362,
47.8945965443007,48.5692813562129,49.24395481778,49.9186284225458,50.5933018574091,
51.2679752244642,51.9426486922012,52.6173221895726,53.2919955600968,53.9666688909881,
55.3157195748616,56.6647706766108,58.0138217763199,59.3628727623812,60.7119088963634,
62.0609449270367,63.4099810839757,64.759017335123,66.1080725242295,67.457127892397,
68.8061816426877,70.1552346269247,71.5043081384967,72.178995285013,72.85368252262,
73.5283710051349,74.2030593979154,74.8777474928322,75.5524356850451,76.2271119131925,
76.9017879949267,77.5764643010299,78.2511407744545,78.9258185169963,79.6004961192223,
80.9495508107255,82.2986215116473,83.6476929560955,84.9967123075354,86.3457302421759,
87.6946363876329,89.0435477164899,90.3928032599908,91.742037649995,93.0918991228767,
94.4417694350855,95.7901865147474,97.138249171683,97.9807547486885,98.823184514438,
99.6655589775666,100.508119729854),.UNSPECIFIED.);
#458=CARTESIAN_POINT('',(108.000102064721,8.88502873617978E-12,16.));
#459=VERTEX_POINT('',#458);
#460=EDGE_CURVE('E10',#459,#459,#457,.T.);
#461=ORIENTED_EDGE('',*,*,#460,.F.);
#462=EDGE_LOOP('',(#461));
#463=FACE_BOUND('',#462,.T.);
#464=ADVANCED_FACE('F54',(#260,#463),#257,.F.);
#465=CARTESIAN_POINT('',(107.96,8.97335862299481E-12,15.9598981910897));
#466=CARTESIAN_POINT('',(107.96,0.219616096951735,15.9598981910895));
#467=CARTESIAN_POINT('',(107.96,0.658848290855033,15.9510606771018));
#468=CARTESIAN_POINT('',(107.96,1.30930266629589,15.9113490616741));
#469=CARTESIAN_POINT('',(107.96,1.95295679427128,15.8458491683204));
#470=CARTESIAN_POINT('',(107.96,5.76765224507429,15.3012269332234));
#471=CARTESIAN_POINT('',(107.96,9.91452695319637,13.0918627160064));
#472=CARTESIAN_POINT('',(107.96,13.3122729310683,8.97936144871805));
#473=CARTESIAN_POINT('',(107.96,14.7952337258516,6.2553630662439));
#474=CARTESIAN_POINT('',(107.96,15.7365176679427,3.25836279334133));
#475=CARTESIAN_POINT('',(107.96,16.0717405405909,3.27600526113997E-07));
#476=CARTESIAN_POINT('',(107.96,15.7365201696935,-3.25836410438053));
#477=CARTESIAN_POINT('',(107.96,14.7952237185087,-6.25535847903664));
#478=CARTESIAN_POINT('',(107.96,13.3123104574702,-8.97937848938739));
#479=CARTESIAN_POINT('',(107.96,11.3518947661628,-11.3518947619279));
#480=CARTESIAN_POINT('',(107.96,8.97937848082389,-13.3123104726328));
#481=CARTESIAN_POINT('',(107.96,6.2553585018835,-14.7952236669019));
#482=CARTESIAN_POINT('',(107.96,3.25836401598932,-15.7365203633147));
#483=CARTESIAN_POINT('',(107.96,-1.79646402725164E-10,-16.0717398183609));
#484=CARTESIAN_POINT('',(107.96,-3.25836401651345,-15.7365203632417));
#485=CARTESIAN_POINT('',(107.96,-6.25535850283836,-14.7952236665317));
#486=CARTESIAN_POINT('',(107.96,-8.97937848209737,-13.3123104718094));
#487=CARTESIAN_POINT('',(107.96,-11.3518947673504,-11.3518947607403));
#488=CARTESIAN_POINT('',(107.96,-13.3123104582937,-8.97937848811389));
#489=CARTESIAN_POINT('',(107.96,-14.795223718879,-6.25535847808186));
#490=CARTESIAN_POINT('',(107.96,-15.7365201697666,-3.25836410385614));
#491=CARTESIAN_POINT('',(107.96,-16.0717405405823,3.27874578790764E-07));
#492=CARTESIAN_POINT('',(107.96,-15.7365176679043,3.2583627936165));
#493=CARTESIAN_POINT('',(107.96,-14.795233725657,6.25536306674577));
#494=CARTESIAN_POINT('',(107.96,-13.3122729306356,8.97936144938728));
#495=CARTESIAN_POINT('',(107.96,-9.91452695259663,13.0918627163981));
#496=CARTESIAN_POINT('',(107.96,-5.76765224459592,15.3012269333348));
#497=CARTESIAN_POINT('',(107.96,-1.9529567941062,15.8458491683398));
#498=CARTESIAN_POINT('',(107.96,-1.30930266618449,15.9113490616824));
#499=CARTESIAN_POINT('',(107.96,-0.658848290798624,15.9510606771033));
#500=CARTESIAN_POINT('',(107.96,-0.219616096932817,15.95989819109));
#501=CARTESIAN_POINT('',(107.96,8.97335862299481E-12,15.9598981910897));
#502=CARTESIAN_POINT('',(107.973333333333,8.94400384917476E-12,15.9732314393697));
#503=CARTESIAN_POINT('',(107.973333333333,0.219799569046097,15.9732314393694));
#504=CARTESIAN_POINT('',(107.973333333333,0.659398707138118,15.9643865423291));
#505=CARTESIAN_POINT('',(107.973333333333,1.3103964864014,15.9246417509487));
#506=CARTESIAN_POINT('',(107.973333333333,1.95458833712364,15.8590871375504));
#507=CARTESIAN_POINT('',(107.973333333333,5.77247066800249,15.3140099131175));
#508=CARTESIAN_POINT('',(107.973333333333,9.92280976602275,13.1027999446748));
#509=CARTESIAN_POINT('',(107.973333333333,13.3233942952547,8.98686300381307));
#510=CARTESIAN_POINT('',(107.973333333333,14.807593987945,6.26058893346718));
#511=CARTESIAN_POINT('',(107.973333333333,15.7496642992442,3.26108490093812));
#512=CARTESIAN_POINT('',(107.973333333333,16.0851672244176,3.27874582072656E-07));
#513=CARTESIAN_POINT('',(107.973333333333,15.7496668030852,-3.2610862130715));
#514=CARTESIAN_POINT('',(107.973333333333,14.8075839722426,-6.2605843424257));
#515=CARTESIAN_POINT('',(107.973333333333,13.3234318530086,-8.98688005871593));
#516=CARTESIAN_POINT('',(107.973333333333,11.3613783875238,-11.3613783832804));
#517=CARTESIAN_POINT('',(107.973333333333,8.98688005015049,-13.3234318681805));
#518=CARTESIAN_POINT('',(107.973333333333,6.26058436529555,-14.8075839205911));
#519=CARTESIAN_POINT('',(107.973333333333,3.2610861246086,-15.7496669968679));
#520=CARTESIAN_POINT('',(107.973333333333,-1.7851377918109E-10,-16.0851665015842));
#521=CARTESIAN_POINT('',(107.973333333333,-3.26108612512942,-15.7496669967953));
#522=CARTESIAN_POINT('',(107.973333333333,-6.26058436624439,-14.8075839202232));
#523=CARTESIAN_POINT('',(107.973333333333,-8.98688005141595,-13.3234318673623));
#524=CARTESIAN_POINT('',(107.973333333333,-11.3613783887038,-11.3613783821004));
#525=CARTESIAN_POINT('',(107.973333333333,-13.3234318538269,-8.98688005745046));
#526=CARTESIAN_POINT('',(107.973333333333,-14.8075839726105,-6.26058434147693));
#527=CARTESIAN_POINT('',(107.973333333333,-15.7496668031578,-3.26108621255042));
#528=CARTESIAN_POINT('',(107.973333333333,-16.0851672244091,3.2814721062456E-07));
#529=CARTESIAN_POINT('',(107.973333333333,-15.7496642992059,3.26108490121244));
#530=CARTESIAN_POINT('',(107.973333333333,-14.8075939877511,6.2605889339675));
#531=CARTESIAN_POINT('',(107.973333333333,-13.3233942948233,8.98686300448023));
#532=CARTESIAN_POINT('',(107.973333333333,-9.92280976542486,13.1027999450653));
#533=CARTESIAN_POINT('',(107.973333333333,-5.77247066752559,15.3140099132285));
#534=CARTESIAN_POINT('',(107.973333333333,-1.95458833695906,15.8590871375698));
#535=CARTESIAN_POINT('',(107.973333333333,-1.31039648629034,15.924641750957));
#536=CARTESIAN_POINT('',(107.973333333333,-0.659398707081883,15.9643865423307));
#537=CARTESIAN_POINT('',(107.973333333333,-0.219799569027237,15.9732314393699));
#538=CARTESIAN_POINT('',(107.973333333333,8.94400384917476E-12,15.9732314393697));
#539=CARTESIAN_POINT('',(107.986666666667,8.91463552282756E-12,15.9865646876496));
#540=CARTESIAN_POINT('',(107.986666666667,0.219983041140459,15.9865646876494));
#541=CARTESIAN_POINT('',(107.986666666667,0.659949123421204,15.9777124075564));
#542=CARTESIAN_POINT('',(107.986666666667,1.3114903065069,15.9379344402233));
#543=CARTESIAN_POINT('',(107.986666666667,1.95621987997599,15.8723251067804));
#544=CARTESIAN_POINT('',(107.986666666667,5.77728909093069,15.3267928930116));
#545=CARTESIAN_POINT('',(107.986666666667,9.93109257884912,13.1137371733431));
#546=CARTESIAN_POINT('',(107.986666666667,13.334515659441,8.9943645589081));
#547=CARTESIAN_POINT('',(107.986666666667,14.8199542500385,6.26581480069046));
#548=CARTESIAN_POINT('',(107.986666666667,15.7628109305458,3.2638070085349));
#549=CARTESIAN_POINT('',(107.986666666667,16.0985939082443,3.28148638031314E-07));
#550=CARTESIAN_POINT('',(107.986666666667,15.7628134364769,-3.26380832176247));
#551=CARTESIAN_POINT('',(107.986666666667,14.8199442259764,-6.26581020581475));
#552=CARTESIAN_POINT('',(107.986666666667,13.3345532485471,-8.99438162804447));
#553=CARTESIAN_POINT('',(107.986666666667,11.3708620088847,-11.370862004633));
#554=CARTESIAN_POINT('',(107.986666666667,8.9943816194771,-13.3345532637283));
#555=CARTESIAN_POINT('',(107.986666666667,6.2658102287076,-14.8199441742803));
#556=CARTESIAN_POINT('',(107.986666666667,3.26380823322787,-15.7628136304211));
#557=CARTESIAN_POINT('',(107.986666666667,-1.77381155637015E-10,-16.0985931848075));
#558=CARTESIAN_POINT('',(107.986666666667,-3.26380823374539,-15.7628136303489));
#559=CARTESIAN_POINT('',(107.986666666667,-6.26581022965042,-14.8199441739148));
#560=CARTESIAN_POINT('',(107.986666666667,-8.99438162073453,-13.3345532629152));
#561=CARTESIAN_POINT('',(107.986666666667,-11.3708620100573,-11.3708620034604));
#562=CARTESIAN_POINT('',(107.986666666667,-13.3345532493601,-8.99438162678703));
#563=CARTESIAN_POINT('',(107.986666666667,-14.819944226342,-6.265810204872));
#564=CARTESIAN_POINT('',(107.986666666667,-15.7628134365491,-3.26380832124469));
#565=CARTESIAN_POINT('',(107.986666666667,-16.0985939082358,3.28419842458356E-07));
#566=CARTESIAN_POINT('',(107.986666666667,-15.7628109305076,3.26380700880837));
#567=CARTESIAN_POINT('',(107.986666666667,-14.8199542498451,6.26581480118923));
#568=CARTESIAN_POINT('',(107.986666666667,-13.334515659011,8.99436455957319));
#569=CARTESIAN_POINT('',(107.986666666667,-9.93109257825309,13.1137371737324));
#570=CARTESIAN_POINT('',(107.986666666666,-5.77728909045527,15.3267928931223));
#571=CARTESIAN_POINT('',(107.986666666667,-1.95621987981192,15.8723251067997));
#572=CARTESIAN_POINT('',(107.986666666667,-1.31149030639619,15.9379344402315));
#573=CARTESIAN_POINT('',(107.986666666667,-0.659949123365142,15.977712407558));
#574=CARTESIAN_POINT('',(107.986666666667,-0.219983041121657,15.9865646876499));
#575=CARTESIAN_POINT('',(107.986666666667,8.91463552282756E-12,15.9865646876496));
#576=CARTESIAN_POINT('',(108.,8.88525364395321E-12,15.9998979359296));
#577=CARTESIAN_POINT('',(108.,0.220166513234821,15.9998979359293));
#578=CARTESIAN_POINT('',(108.,0.660499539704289,15.9910382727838));
#579=CARTESIAN_POINT('',(108.,1.31258412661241,15.9512271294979));
#580=CARTESIAN_POINT('',(108.,1.95785142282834,15.8855630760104));
#581=CARTESIAN_POINT('',(108.,5.78210751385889,15.3395758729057));
#582=CARTESIAN_POINT('',(108.,9.9393753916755,13.1246744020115));
#583=CARTESIAN_POINT('',(108.,13.3456370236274,9.00186611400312));
#584=CARTESIAN_POINT('',(108.,14.8323145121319,6.27104066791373));
#585=CARTESIAN_POINT('',(108.,15.7759575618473,3.26652911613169));
#586=CARTESIAN_POINT('',(108.,16.112020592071,3.28422693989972E-07));
#587=CARTESIAN_POINT('',(108.,15.7759600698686,-3.26653043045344));
#588=CARTESIAN_POINT('',(108.,14.8323044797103,-6.2710360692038));
#589=CARTESIAN_POINT('',(108.,13.3456746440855,-9.00188319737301));
#590=CARTESIAN_POINT('',(108.,11.3803456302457,-11.3803456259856));
#591=CARTESIAN_POINT('',(108.,9.00188318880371,-13.345674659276));
#592=CARTESIAN_POINT('',(108.,6.27103609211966,-14.8323044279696));
#593=CARTESIAN_POINT('',(108.,3.26653034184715,-15.7759602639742));
#594=CARTESIAN_POINT('',(108.,-1.76248532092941E-10,-16.1120198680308));
#595=CARTESIAN_POINT('',(108.,-3.26653034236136,-15.7759602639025));
#596=CARTESIAN_POINT('',(108.,-6.27103609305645,-14.8323044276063));
#597=CARTESIAN_POINT('',(108.,-9.0018831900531,-13.3456746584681));
#598=CARTESIAN_POINT('',(108.,-11.3803456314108,-11.3803456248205));
#599=CARTESIAN_POINT('',(108.,-13.3456746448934,-9.0018831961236));
#600=CARTESIAN_POINT('',(108.,-14.8323044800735,-6.27103606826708));
#601=CARTESIAN_POINT('',(108.,-15.7759600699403,-3.26653042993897));
#602=CARTESIAN_POINT('',(108.,-16.1120205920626,3.28692474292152E-07));
#603=CARTESIAN_POINT('',(108.,-15.7759575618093,3.26652911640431));
#604=CARTESIAN_POINT('',(108.,-14.8323145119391,6.27104066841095));
#605=CARTESIAN_POINT('',(108.,-13.3456370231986,9.00186611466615));
#606=CARTESIAN_POINT('',(108.,-9.93937539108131,13.1246744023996));
#607=CARTESIAN_POINT('',(108.,-5.78210751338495,15.339575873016));
#608=CARTESIAN_POINT('',(108.,-1.95785142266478,15.8855630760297));
#609=CARTESIAN_POINT('',(108.,-1.31258412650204,15.9512271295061));
#610=CARTESIAN_POINT('',(108.,-0.660499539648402,15.9910382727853));
#611=CARTESIAN_POINT('',(108.,-0.220166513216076,15.9998979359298));
#612=CARTESIAN_POINT('',(108.,8.88525364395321E-12,15.9998979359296));
#613=CARTESIAN_POINT('',(109.333333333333,5.94714707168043E-12,17.3332227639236));
#614=CARTESIAN_POINT('',(109.333333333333,0.238513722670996,17.3332227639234));
#615=CARTESIAN_POINT('',(109.333333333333,0.715541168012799,17.3236247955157));
#616=CARTESIAN_POINT('',(109.333333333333,1.42196613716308,17.280496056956));
#617=CARTESIAN_POINT('',(109.333333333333,2.1210057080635,17.2093599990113));
#618=CARTESIAN_POINT('',(109.333333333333,6.26394980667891,16.6178738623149));
#619=CARTESIAN_POINT('',(109.333333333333,10.7676566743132,14.2183972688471));
#620=CARTESIAN_POINT('',(109.333333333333,14.4577734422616,9.75202162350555));
#621=CARTESIAN_POINT('',(109.333333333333,16.0683407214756,6.79362739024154));
#622=CARTESIAN_POINT('',(109.333333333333,17.0906206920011,3.53873987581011));
#623=CARTESIAN_POINT('',(109.333333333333,17.4546889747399,3.55828289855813E-07));
#624=CARTESIAN_POINT('',(109.333333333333,17.0906234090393,-3.53874129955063));
#625=CARTESIAN_POINT('',(109.333333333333,16.0683298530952,-6.79362240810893));
#626=CARTESIAN_POINT('',(109.333333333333,14.4578141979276,-9.75204013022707));
#627=CARTESIAN_POINT('',(109.333333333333,12.3287077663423,-12.3287077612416));
#628=CARTESIAN_POINT('',(109.333333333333,9.75204012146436,-14.4578142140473));
#629=CARTESIAN_POINT('',(109.333333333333,6.79362243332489,-16.0683297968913));
#630=CARTESIAN_POINT('',(109.333333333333,3.53874120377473,-17.0906236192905));
#631=CARTESIAN_POINT('',(109.333333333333,-6.29861776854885E-11,-17.4546881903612));
#632=CARTESIAN_POINT('',(109.333333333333,-3.53874120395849,-17.0906236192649));
#633=CARTESIAN_POINT('',(109.333333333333,-6.79362243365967,-16.0683297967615));
#634=CARTESIAN_POINT('',(109.333333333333,-9.75204012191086,-14.4578142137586));
#635=CARTESIAN_POINT('',(109.333333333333,-12.3287077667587,-12.3287077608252));
#636=CARTESIAN_POINT('',(109.333333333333,-14.4578141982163,-9.75204012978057));
#637=CARTESIAN_POINT('',(109.333333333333,-16.068329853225,-6.79362240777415));
#638=CARTESIAN_POINT('',(109.333333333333,-17.0906234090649,-3.53874129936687));
#639=CARTESIAN_POINT('',(109.333333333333,-17.45468897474,3.55955657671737E-07));
#640=CARTESIAN_POINT('',(109.333333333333,-17.0906206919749,3.53873987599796));
#641=CARTESIAN_POINT('',(109.333333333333,-16.0683407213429,6.79362739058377));
#642=CARTESIAN_POINT('',(109.333333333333,-14.4577734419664,9.75202162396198));
#643=CARTESIAN_POINT('',(109.333333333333,-10.7676566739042,14.2183972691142));
#644=CARTESIAN_POINT('',(109.333333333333,-6.26394980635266,16.6178738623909));
#645=CARTESIAN_POINT('',(109.333333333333,-2.12100570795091,17.2093599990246));
#646=CARTESIAN_POINT('',(109.333333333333,-1.42196613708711,17.2804960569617));
#647=CARTESIAN_POINT('',(109.333333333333,-0.71554116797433,17.3236247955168));
#648=CARTESIAN_POINT('',(109.333333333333,-0.238513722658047,17.3332227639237));
#649=CARTESIAN_POINT('',(109.333333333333,5.94714707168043E-12,17.3332227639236));
#650=CARTESIAN_POINT('',(110.666666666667,3.00820024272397E-12,18.6665475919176));
#651=CARTESIAN_POINT('',(110.666666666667,0.256860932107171,18.6665475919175));
#652=CARTESIAN_POINT('',(110.666666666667,0.770582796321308,18.6562113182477));
#653=CARTESIAN_POINT('',(110.666666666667,1.53134814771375,18.6097649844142));
#654=CARTESIAN_POINT('',(110.666666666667,2.28415999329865,18.5331569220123));
#655=CARTESIAN_POINT('',(110.666666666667,6.74579209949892,17.8961718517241));
#656=CARTESIAN_POINT('',(110.666666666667,11.5959379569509,15.3121201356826));
#657=CARTESIAN_POINT('',(110.666666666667,15.5699098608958,10.502177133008));
#658=CARTESIAN_POINT('',(110.666666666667,17.3043669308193,7.31621411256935));
#659=CARTESIAN_POINT('',(110.666666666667,18.4052838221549,3.81095063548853));
#660=CARTESIAN_POINT('',(110.666666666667,18.7973573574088,3.83233883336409E-07));
#661=CARTESIAN_POINT('',(110.666666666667,18.4052867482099,-3.81095216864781));
#662=CARTESIAN_POINT('',(110.666666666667,17.3043552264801,-7.31620874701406));
#663=CARTESIAN_POINT('',(110.666666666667,15.5699537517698,-10.5021970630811));
#664=CARTESIAN_POINT('',(110.666666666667,13.2770699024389,-13.2770698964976));
#665=CARTESIAN_POINT('',(110.666666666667,10.502197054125,-15.5699537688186));
#666=CARTESIAN_POINT('',(110.666666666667,7.31620877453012,-17.3043551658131));
#667=CARTESIAN_POINT('',(110.666666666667,3.81095206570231,-18.4052869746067));
#668=CARTESIAN_POINT('',(110.666666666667,5.02779114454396E-11,-18.7973565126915));
#669=CARTESIAN_POINT('',(110.666666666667,-3.81095206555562,-18.4052869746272));
#670=CARTESIAN_POINT('',(110.666666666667,-7.31620877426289,-17.3043551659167));
#671=CARTESIAN_POINT('',(110.666666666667,-10.5021970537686,-15.5699537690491));
#672=CARTESIAN_POINT('',(110.666666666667,-13.2770699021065,-13.2770698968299));
#673=CARTESIAN_POINT('',(110.666666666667,-15.5699537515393,-10.5021970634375));
#674=CARTESIAN_POINT('',(110.666666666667,-17.3043552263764,-7.31620874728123));
#675=CARTESIAN_POINT('',(110.666666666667,-18.4052867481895,-3.81095216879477));
#676=CARTESIAN_POINT('',(110.666666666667,-18.7973573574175,3.83218839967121E-07));
#677=CARTESIAN_POINT('',(110.666666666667,-18.4052838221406,3.81095063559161));
#678=CARTESIAN_POINT('',(110.666666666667,-17.3043669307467,7.31621411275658));
#679=CARTESIAN_POINT('',(110.666666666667,-15.5699098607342,10.5021771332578));
#680=CARTESIAN_POINT('',(110.666666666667,-11.595937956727,15.3121201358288));
#681=CARTESIAN_POINT('',(110.666666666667,-6.74579209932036,17.8961718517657));
#682=CARTESIAN_POINT('',(110.666666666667,-2.28415999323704,18.5331569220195));
#683=CARTESIAN_POINT('',(110.666666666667,-1.53134814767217,18.6097649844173));
#684=CARTESIAN_POINT('',(110.666666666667,-0.77058279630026,18.6562113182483));
#685=CARTESIAN_POINT('',(110.666666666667,-0.256860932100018,18.6665475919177));
#686=CARTESIAN_POINT('',(110.666666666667,3.00820024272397E-12,18.6665475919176));
#687=CARTESIAN_POINT('',(112.,0.,19.9998724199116));
#688=CARTESIAN_POINT('',(112.,0.275208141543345,19.9998724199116));
#689=CARTESIAN_POINT('',(112.,0.825624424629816,19.9887978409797));
#690=CARTESIAN_POINT('',(112.,1.64073015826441,19.9390339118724));
#691=CARTESIAN_POINT('',(112.,2.44731427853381,19.8569538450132));
#692=CARTESIAN_POINT('',(112.,7.22763439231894,19.1744698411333));
#693=CARTESIAN_POINT('',(112.,12.4242192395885,16.4058430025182));
#694=CARTESIAN_POINT('',(112.,16.68204627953,11.2523326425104));
#695=CARTESIAN_POINT('',(112.,18.540393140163,7.83880083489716));
#696=CARTESIAN_POINT('',(112.,19.7199469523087,4.08316139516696));
#697=CARTESIAN_POINT('',(112.,20.1400257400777,4.10639478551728E-07));
#698=CARTESIAN_POINT('',(112.,19.7199500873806,-4.08316303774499));
#699=CARTESIAN_POINT('',(112.,18.540380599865,-7.83879508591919));
#700=CARTESIAN_POINT('',(112.,16.6820933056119,-11.2523539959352));
#701=CARTESIAN_POINT('',(112.,14.2254320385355,-14.2254320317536));
#702=CARTESIAN_POINT('',(112.,11.2523539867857,-16.6820933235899));
#703=CARTESIAN_POINT('',(112.,7.83879511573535,-18.5403805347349));
#704=CARTESIAN_POINT('',(112.,4.08316292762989,-19.719950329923));
#705=CARTESIAN_POINT('',(112.,1.63540049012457E-10,-20.1400248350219));
#706=CARTESIAN_POINT('',(112.,-4.08316292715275,-19.7199503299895));
#707=CARTESIAN_POINT('',(112.,-7.8387951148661,-18.5403805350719));
#708=CARTESIAN_POINT('',(112.,-11.2523539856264,-16.6820933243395));
#709=CARTESIAN_POINT('',(112.,-14.2254320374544,-14.2254320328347));
#710=CARTESIAN_POINT('',(112.,-16.6820933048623,-11.2523539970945));
#711=CARTESIAN_POINT('',(112.,-18.5403805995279,-7.8387950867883));
#712=CARTESIAN_POINT('',(112.,-19.7199500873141,-4.08316303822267));
#713=CARTESIAN_POINT('',(112.,-20.1400257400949,4.10482022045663E-07));
#714=CARTESIAN_POINT('',(112.,-19.7199469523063,4.08316139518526));
#715=CARTESIAN_POINT('',(112.,-18.5403931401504,7.83880083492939));
#716=CARTESIAN_POINT('',(112.,-16.6820462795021,11.2523326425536));
#717=CARTESIAN_POINT('',(112.,-12.4242192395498,16.4058430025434));
#718=CARTESIAN_POINT('',(112.,-7.22763439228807,19.1744698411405));
#719=CARTESIAN_POINT('',(112.,-2.44731427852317,19.8569538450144));
#720=CARTESIAN_POINT('',(112.,-1.64073015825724,19.9390339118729));
#721=CARTESIAN_POINT('',(112.,-0.825624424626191,19.9887978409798));
#722=CARTESIAN_POINT('',(112.,-0.275208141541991,19.9998724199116));
#723=CARTESIAN_POINT('',(112.,0.,19.9998724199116));
#724=B_SPLINE_SURFACE_WITH_KNOTS('',3,3,((#465,#466,#467,#468,#469,#470,#471,#472,#473,#474,
#475,#476,#477,#478,#479,#480,#481,#482,#483,#484,#485,#486,#487,#488,#489,#490,#491,#492,#493,
#494,#495,#496,#497,#498,#499,#500,#501),(#502,#503,#504,#505,#506,#507,#508,#509,#510,#511,
#512,#513,#514,#515,#516,#517,#518,#519,#520,#521,#522,#523,#524,#525,#526,#527,#528,#529,#530,
#531,#532,#533,#534,#535,#536,#537,#538),(#539,#540,#541,#542,#543,#544,#545,#546,#547,#548,
#549,#550,#551,#552,#553,#554,#555,#556,#557,#558,#559,#560,#561,#562,#563,#564,#565,#566,#567,
#568,#569,#570,#571,#572,#573,#574,#575),(#576,#577,#578,#579,#580,#581,#582,#583,#584,#585,
#586,#587,#588,#589,#590,#591,#592,#593,#594,#595,#596,#597,#598,#599,#600,#601,#602,#603,#604,
#605,#606,#607,#608,#609,#610,#611,#612),(#613,#614,#615,#616,#617,#618,#619,#620,#621,#622,
#623,#624,#625,#626,#627,#628,#629,#630,#631,#632,#633,#634,#635,#636,#637,#638,#639,#640,#641,
#642,#643,#644,#645,#646,#647,#648,#649),(#650,#651,#652,#653,#654,#655,#656,#657,#658,#659,
#660,#661,#662,#663,#664,#665,#666,#667,#668,#669,#670,#671,#672,#673,#674,#675,#676,#677,#678,
#679,#680,#681,#682,#683,#684,#685,#686),(#687,#688,#689,#690,#691,#692,#693,#694,#695,#696,
#697,#698,#699,#700,#701,#702,#703,#704,#705,#706,#707,#708,#709,#710,#711,#712,#713,#714,#715,
#716,#717,#718,#719,#720,#721,#722,#723)),.UNSPECIFIED.,.F.,.T.,.F.,(4,3,4),(4,1,1,1,1,1,1,1,1,
1,1,1,1,1,1,1,1,1,1,1,1,1,1,1,1,1,1,1,1,1,1,1,1,1,4),(-0.01,0.,1.),(0.,0.00625000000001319,
0.0125000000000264,0.0187500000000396,0.0250000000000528,0.125000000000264,0.156250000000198,
0.187500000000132,0.218750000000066,0.25,0.28125,0.3125,0.34375,0.375,0.40625,0.4375,0.46875,
0.5,0.531249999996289,0.562499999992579,0.593749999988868,0.624999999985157,0.656249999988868,
0.687499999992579,0.718749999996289,0.75,0.781250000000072,0.812500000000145,0.843750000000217,
0.875000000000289,0.975000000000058,0.981250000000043,0.987500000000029,0.993750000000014,1.),.UNSPECIFIED.);
#725=CARTESIAN_POINT('',(108.000102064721,8.88502873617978E-12,16.));
#726=CARTESIAN_POINT('',(108.041767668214,8.79321524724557E-12,16.0416653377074));
#727=CARTESIAN_POINT('',(108.083433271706,8.70140093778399E-12,16.0833306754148));
#728=CARTESIAN_POINT('',(108.166764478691,8.51777066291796E-12,16.1666613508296));
#729=CARTESIAN_POINT('',(108.208430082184,8.42595469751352E-12,16.208326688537));
#730=CARTESIAN_POINT('',(108.291761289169,8.24232109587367E-12,16.2916573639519));
#731=CARTESIAN_POINT('',(108.333426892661,8.15050345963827E-12,16.3333227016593));
#732=CARTESIAN_POINT('',(108.416758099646,7.96686650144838E-12,16.4166533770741));
#733=CARTESIAN_POINT('',(108.458423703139,7.87504717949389E-12,16.4583187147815));
#734=CARTESIAN_POINT('',(108.541754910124,7.69140683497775E-12,16.5416493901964));
#735=CARTESIAN_POINT('',(108.583420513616,7.5995858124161E-12,16.5833147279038));
#736=CARTESIAN_POINT('',(108.666751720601,7.41594205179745E-12,16.6666454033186));
#737=CARTESIAN_POINT('',(108.708417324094,7.32411931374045E-12,16.708310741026));
#738=CARTESIAN_POINT('',(108.791748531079,7.14047210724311E-12,16.7916414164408));
#739=CARTESIAN_POINT('',(108.833414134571,7.04864763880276E-12,16.8333067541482));
#740=CARTESIAN_POINT('',(108.916745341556,6.86499695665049E-12,16.9166374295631));
#741=CARTESIAN_POINT('',(108.958410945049,6.77317074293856E-12,16.9583027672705));
#742=CARTESIAN_POINT('',(109.041742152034,6.58951655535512E-12,17.0416334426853));
#743=CARTESIAN_POINT('',(109.083407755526,6.49768858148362E-12,17.0832987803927));
#744=CARTESIAN_POINT('',(109.166738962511,6.31403085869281E-12,17.1666294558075));
#745=CARTESIAN_POINT('',(109.208404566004,6.2222011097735E-12,17.208294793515));
#746=CARTESIAN_POINT('',(109.291735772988,6.03853982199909E-12,17.2916254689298));
#747=CARTESIAN_POINT('',(109.333401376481,5.94670828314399E-12,17.3332908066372));
#748=CARTESIAN_POINT('',(109.416732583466,5.76304340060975E-12,17.416621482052));
#749=CARTESIAN_POINT('',(109.458398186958,5.67121005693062E-12,17.4582868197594));
#750=CARTESIAN_POINT('',(109.541729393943,5.48754154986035E-12,17.5416174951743));
#751=CARTESIAN_POINT('',(109.583394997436,5.3957063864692E-12,17.5832828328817));
#752=CARTESIAN_POINT('',(109.666726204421,5.21203422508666E-12,17.6666135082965));
#753=CARTESIAN_POINT('',(109.708391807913,5.12019722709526E-12,17.7082788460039));
#754=CARTESIAN_POINT('',(109.791723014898,4.93652138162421E-12,17.7916095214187));
#755=CARTESIAN_POINT('',(109.833388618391,4.84468253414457E-12,17.8332748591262));
#756=CARTESIAN_POINT('',(109.916719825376,4.66100297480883E-12,17.916605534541));
#757=CARTESIAN_POINT('',(109.958385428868,4.56916226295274E-12,17.9582708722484));
#758=CARTESIAN_POINT('',(110.041716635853,4.38547895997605E-12,18.0416015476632));
#759=CARTESIAN_POINT('',(110.083382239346,4.29363636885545E-12,18.0832668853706));
#760=CARTESIAN_POINT('',(110.166713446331,4.10994929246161E-12,18.1665975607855));
#761=CARTESIAN_POINT('',(110.208379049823,4.01810480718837E-12,18.2082628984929));
#762=CARTESIAN_POINT('',(110.291710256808,3.83441392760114E-12,18.2915935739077));
#763=CARTESIAN_POINT('',(110.333375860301,3.74256753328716E-12,18.3332589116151));
#764=CARTESIAN_POINT('',(110.416707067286,3.55887282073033E-12,18.4165895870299));
#765=CARTESIAN_POINT('',(110.458372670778,3.46702450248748E-12,18.4582549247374));
#766=CARTESIAN_POINT('',(110.541703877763,3.28332592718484E-12,18.5415856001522));
#767=CARTESIAN_POINT('',(110.583369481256,3.19147567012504E-12,18.5832509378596));
#768=CARTESIAN_POINT('',(110.66670068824,3.00777320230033E-12,18.6665816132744));
#769=CARTESIAN_POINT('',(110.708366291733,2.91592099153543E-12,18.7082469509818));
#770=CARTESIAN_POINT('',(110.791697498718,2.73221460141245E-12,18.7915776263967));
#771=CARTESIAN_POINT('',(110.83336310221,2.64036042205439E-12,18.8332429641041));
#772=CARTESIAN_POINT('',(110.916694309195,2.45665007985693E-12,18.9165736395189));
#773=CARTESIAN_POINT('',(110.958359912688,2.36479391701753E-12,18.9582389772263));
#774=CARTESIAN_POINT('',(111.041691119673,2.18107959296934E-12,19.0415696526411));
#775=CARTESIAN_POINT('',(111.083356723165,2.08922143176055E-12,19.0832349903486));
#776=CARTESIAN_POINT('',(111.16668793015,1.90550309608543E-12,19.1665656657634));
#777=CARTESIAN_POINT('',(111.208353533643,1.8136429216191E-12,19.2082310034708));
#778=CARTESIAN_POINT('',(111.291684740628,1.62992054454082E-12,19.2915616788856));
#779=CARTESIAN_POINT('',(111.33335034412,1.53805834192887E-12,19.333227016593));
#780=CARTESIAN_POINT('',(111.416681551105,1.3543318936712E-12,19.4165576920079));
#781=CARTESIAN_POINT('',(111.458347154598,1.26246764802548E-12,19.4582230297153));
#782=CARTESIAN_POINT('',(111.541678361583,1.07873709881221E-12,19.5415537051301));
#783=CARTESIAN_POINT('',(111.583343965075,9.8687079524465E-13,19.5832190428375));
#784=CARTESIAN_POINT('',(111.66667517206,8.03136115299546E-13,19.6665497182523));
#785=CARTESIAN_POINT('',(111.708340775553,7.11267738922E-13,19.7082150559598));
#786=CARTESIAN_POINT('',(111.791671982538,5.27528898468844E-13,19.7915457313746));
#787=CARTESIAN_POINT('',(111.83333758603,4.35658434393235E-13,19.833211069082));
#788=CARTESIAN_POINT('',(111.916668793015,2.51915403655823E-13,19.9165417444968));
#789=CARTESIAN_POINT('',(111.958334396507,1.60042836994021E-13,19.9582070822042));
#790=CARTESIAN_POINT('',(112.,0.,19.9998724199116));
#791=B_SPLINE_CURVE_WITH_KNOTS('',3,(#725,#726,#727,#728,#729,#730,#731,#732,#733,#734,#735,
#736,#737,#738,#739,#740,#741,#742,#743,#744,#745,#746,#747,#748,#749,#750,#751,#752,#753,#754,
#755,#756,#757,#758,#759,#760,#761,#762,#763,#764,#765,#766,#767,#768,#769,#770,#771,#772,#773,
#774,#775,#776,#777,#778,#779,#780,#781,#782,#783,#784,#785,#786,#787,#788,#789,#790),
.UNSPECIFIED.,.F.,.F.,(4,2,2,2,2,2,2,2,2,2,2,2,2,2,2,2,2,2,2,2,2,2,2,2,2,2,2,2,2,2,2,2,4),(0.,
0.176771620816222,0.353543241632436,0.530314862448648,0.707086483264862,0.883858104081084,
1.06062972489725,1.2374013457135,1.41417296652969,1.59094458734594,1.76771620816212,
1.94448782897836,2.12125944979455,2.2980310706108,2.47480269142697,2.65157431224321,
2.82834593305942,3.00511755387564,3.18188917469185,3.35866079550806,3.53543241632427,
3.7122040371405,3.8889756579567,4.06574727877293,4.24251889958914,4.41929052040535,
4.59606214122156,4.77283376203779,4.94960538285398,5.12637700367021,5.30314862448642,
5.47992024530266,5.65669186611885),.UNSPECIFIED.);
#792=EDGE_CURVE('BSEAM31',#459,#236,#791,.T.);
#793=ORIENTED_EDGE('',*,*,#460,.T.);
#794=ORIENTED_EDGE('',*,*,#237,.T.);
#795=ORIENTED_EDGE('',*,*,#792,.T.);
#796=ORIENTED_EDGE('',*,*,#792,.F.);
#797=EDGE_LOOP('',(#793,#795,#794,#796));
#798=FACE_BOUND('',#797,.T.);
#799=ADVANCED_FACE('F31',(#798),#724,.T.);
#800=CLOSED_SHELL('',(#252,#464,#799));
#801=MANIFOLD_SOLID_BREP('B2',#800);
#802=ADVANCED_BREP_SHAPE_REPRESENTATION('',(#18,#801),#14);
#803=SHAPE_DEFINITION_REPRESENTATION(#9,#802);
ENDSEC;
END-ISO-10303-21;
